VERSION 5.8 ;
BUSBITCHARS "[]" ;
DIVIDERCHAR "/" ;
UNITS
    DATABASE MICRONS 1000 ;
END UNITS

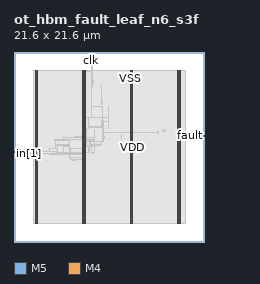
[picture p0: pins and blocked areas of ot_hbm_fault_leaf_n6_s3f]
MACRO ot_hbm_fault_leaf_n6_s3f
  FOREIGN ot_hbm_fault_leaf_n6_s3f 0 0 ;
  CLASS BLOCK ;
  SIZE 21.6 BY 21.6 ;
  PIN clk
    DIRECTION INPUT ;
    USE SIGNAL ;
    PORT
      LAYER M5 ;
        RECT  8.784 21.516 8.808 21.6 ;
    END
  END clk
  PIN fault
    DIRECTION OUTPUT ;
    USE SIGNAL ;
    PORT
      LAYER M4 ;
        RECT  21.516 12.048 21.6 12.072 ;
    END
    PORT
      LAYER M4 ;
        RECT  20.473 12.048 21.564 12.072 ;
    END
  END fault
  PIN in[0]
    DIRECTION INPUT ;
    USE SIGNAL ;
    PORT
      LAYER M4 ;
        RECT  0 9.936 0.084 9.96 ;
    END
  END in[0]
  PIN in[1]
    DIRECTION INPUT ;
    USE SIGNAL ;
    PORT
      LAYER M4 ;
        RECT  0 10.032 0.084 10.056 ;
    END
  END in[1]
  PIN in[2]
    DIRECTION INPUT ;
    USE SIGNAL ;
    PORT
      LAYER M4 ;
        RECT  0 10.128 0.084 10.152 ;
    END
  END in[2]
  PIN in[3]
    DIRECTION INPUT ;
    USE SIGNAL ;
    PORT
      LAYER M4 ;
        RECT  0 10.224 0.084 10.248 ;
    END
  END in[3]
  PIN in[4]
    DIRECTION INPUT ;
    USE SIGNAL ;
    PORT
      LAYER M4 ;
        RECT  0 10.32 0.084 10.344 ;
    END
  END in[4]
  PIN in[5]
    DIRECTION INPUT ;
    USE SIGNAL ;
    PORT
      LAYER M4 ;
        RECT  0 10.416 0.084 10.44 ;
    END
  END in[5]
  PIN rst_n
    DIRECTION INPUT ;
    USE SIGNAL ;
    PORT
      LAYER M5 ;
        RECT  8.88 21.516 8.904 21.6 ;
    END
  END rst_n
  PIN VDD
    DIRECTION INOUT ;
    USE POWER ;
    PORT
      LAYER M5 ;
        RECT  18.792 2.151 18.912 19.449 ;
        RECT  13.392 2.151 13.512 19.449 ;
        RECT  7.992 2.151 8.112 19.449 ;
        RECT  2.592 2.151 2.712 19.449 ;
    END
  END VDD
  PIN VSS
    DIRECTION INOUT ;
    USE GROUND ;
    PORT
      LAYER M5 ;
        RECT  18.6 2.137 18.72 19.463 ;
        RECT  13.2 2.137 13.32 19.463 ;
        RECT  7.8 2.137 7.92 19.463 ;
        RECT  2.4 2.137 2.52 19.463 ;
    END
  END VSS
  # OT_OBS_CLOSED layer=M5 d_um=1.536 added=2
  OBS
    LAYER RVTN ;
     RECT  2.16 2.16 19.44 2.295 ;
     RECT  2.16 2.565 19.44 2.835 ;
     RECT  2.16 3.105 19.44 3.375 ;
     RECT  2.16 3.645 19.44 3.915 ;
     RECT  2.16 4.185 19.44 4.455 ;
     RECT  2.16 4.725 19.44 4.995 ;
     RECT  2.16 5.265 19.44 5.535 ;
     RECT  2.16 5.805 19.44 6.075 ;
     RECT  2.16 6.345 19.44 6.615 ;
     RECT  2.16 6.885 19.44 7.155 ;
     RECT  2.16 7.425 19.44 7.695 ;
     RECT  2.16 7.965 19.44 8.235 ;
     RECT  2.16 8.505 19.44 8.775 ;
     RECT  2.16 9.045 19.44 9.315 ;
     RECT  2.16 9.585 19.44 9.855 ;
     RECT  2.16 10.125 19.44 10.395 ;
     RECT  2.16 10.665 19.44 10.935 ;
     RECT  2.16 11.205 19.44 11.475 ;
     RECT  2.16 11.745 19.44 12.015 ;
     RECT  2.16 12.285 19.44 12.555 ;
     RECT  2.16 12.825 19.44 13.095 ;
     RECT  2.16 13.365 19.44 13.635 ;
     RECT  2.16 13.905 19.44 14.175 ;
     RECT  2.16 14.445 19.44 14.715 ;
     RECT  2.16 14.985 19.44 15.255 ;
     RECT  2.16 15.525 19.44 15.795 ;
     RECT  2.16 16.065 19.44 16.335 ;
     RECT  2.16 16.605 19.44 16.875 ;
     RECT  2.16 17.145 19.44 17.415 ;
     RECT  2.16 17.685 19.44 17.955 ;
     RECT  2.16 18.225 19.44 18.495 ;
     RECT  2.16 18.765 19.44 19.035 ;
     RECT  2.16 19.305 19.44 19.44 ;
    LAYER RVTP ;
     RECT  2.16 2.295 19.44 2.565 ;
     RECT  2.16 2.835 19.44 3.105 ;
     RECT  2.16 3.375 19.44 3.645 ;
     RECT  2.16 3.915 19.44 4.185 ;
     RECT  2.16 4.455 19.44 4.725 ;
     RECT  2.16 4.995 19.44 5.265 ;
     RECT  2.16 5.535 19.44 5.805 ;
     RECT  2.16 6.075 19.44 6.345 ;
     RECT  2.16 6.615 19.44 6.885 ;
     RECT  2.16 7.155 19.44 7.425 ;
     RECT  2.16 7.695 19.44 7.965 ;
     RECT  2.16 8.235 19.44 8.505 ;
     RECT  2.16 8.775 19.44 9.045 ;
     RECT  2.16 9.315 19.44 9.585 ;
     RECT  2.16 9.855 19.44 10.125 ;
     RECT  2.16 10.395 19.44 10.665 ;
     RECT  2.16 10.935 19.44 11.205 ;
     RECT  2.16 11.475 19.44 11.745 ;
     RECT  2.16 12.015 19.44 12.285 ;
     RECT  2.16 12.555 19.44 12.825 ;
     RECT  2.16 13.095 19.44 13.365 ;
     RECT  2.16 13.635 19.44 13.905 ;
     RECT  2.16 14.175 19.44 14.445 ;
     RECT  2.16 14.715 19.44 14.985 ;
     RECT  2.16 15.255 19.44 15.525 ;
     RECT  2.16 15.795 19.44 16.065 ;
     RECT  2.16 16.335 19.44 16.605 ;
     RECT  2.16 16.875 19.44 17.145 ;
     RECT  2.16 17.415 19.44 17.685 ;
     RECT  2.16 17.955 19.44 18.225 ;
     RECT  2.16 18.495 19.44 18.765 ;
     RECT  2.16 19.035 19.44 19.305 ;
    LAYER M1 ;
     RECT  2.16 2.151 19.44 19.449 ;
    LAYER M2 ;
     RECT  2.16 2.151 19.44 19.449 ;
     RECT  19.44 12.186 20.507 12.204 ;
    LAYER M3 ;
     RECT  2.415 2.143 2.505 2.413 ;
     RECT  7.815 2.143 7.905 2.413 ;
     RECT  13.215 2.143 13.305 2.413 ;
     RECT  18.615 2.143 18.705 2.413 ;
     RECT  6.624 9.211 6.642 9.319 ;
     RECT  6.624 9.319 7.002 9.355 ;
     RECT  7.815 2.413 8.097 9.355 ;
     RECT  6.624 9.355 8.097 9.391 ;
     RECT  6.408 9.391 8.097 9.625 ;
     RECT  5.4 9.859 5.418 9.895 ;
     RECT  6.3 9.625 8.097 9.895 ;
     RECT  2.415 2.413 2.697 9.931 ;
     RECT  4.5 9.895 8.097 9.931 ;
     RECT  8.82 10.057 8.838 10.093 ;
     RECT  4.068 9.931 8.097 10.121 ;
     RECT  2.304 9.931 2.697 10.129 ;
     RECT  8.82 10.093 8.982 10.201 ;
     RECT  0.144 10.075 0.162 10.253 ;
     RECT  2.304 10.129 3.222 10.391 ;
     RECT  4.068 10.121 4.914 10.589 ;
     RECT  2.304 10.391 2.697 10.625 ;
     RECT  5.652 10.121 8.097 10.843 ;
     RECT  8.82 10.201 9.198 10.843 ;
     RECT  5.652 10.843 9.198 10.975 ;
     RECT  4.716 10.589 4.914 11.011 ;
     RECT  5.652 10.975 9.522 11.011 ;
     RECT  4.716 11.011 9.954 11.129 ;
     RECT  9.936 11.129 9.954 11.273 ;
     RECT  4.716 11.129 9.126 11.515 ;
     RECT  4.644 11.515 9.126 11.669 ;
     RECT  5.328 11.669 9.126 11.705 ;
     RECT  10.8 11.641 10.818 11.777 ;
     RECT  5.58 11.705 9.126 11.849 ;
     RECT  6.84 11.849 8.097 11.939 ;
     RECT  6.84 11.939 6.858 11.975 ;
     RECT  10.116 11.785 10.278 11.975 ;
     RECT  10.116 11.975 10.134 11.981 ;
     RECT  20.484 12.043 20.502 12.209 ;
     RECT  12.168 11.749 12.186 12.245 ;
     RECT  18.615 2.413 18.897 12.361 ;
     RECT  16.452 12.181 16.47 12.475 ;
     RECT  18.396 12.361 18.897 12.479 ;
     RECT  16.272 12.475 16.47 12.551 ;
     RECT  16.848 12.559 16.866 12.595 ;
     RECT  16.848 12.595 17.262 12.749 ;
     RECT  9.108 11.849 9.126 12.785 ;
     RECT  16.848 12.749 16.866 12.785 ;
     RECT  7.815 11.939 8.097 12.955 ;
     RECT  7.815 12.955 8.226 13.019 ;
     RECT  10.728 12.901 10.746 13.675 ;
     RECT  10.044 13.675 10.746 14.099 ;
     RECT  9.756 14.203 9.774 14.243 ;
     RECT  10.728 14.099 10.746 14.369 ;
     RECT  9.828 15.403 9.846 15.449 ;
     RECT  10.764 14.485 10.782 15.449 ;
     RECT  9.972 15.601 10.098 15.989 ;
     RECT  9.972 15.989 9.99 17.609 ;
     RECT  9.828 17.725 9.846 17.879 ;
     RECT  8.892 17.659 8.91 18.031 ;
     RECT  8.892 18.031 9.054 18.419 ;
     RECT  2.415 10.625 2.697 19.187 ;
     RECT  7.815 13.019 8.097 19.187 ;
     RECT  13.215 2.413 13.497 19.187 ;
     RECT  18.615 12.479 18.897 19.187 ;
     RECT  8.892 18.419 8.91 19.373 ;
     RECT  2.415 19.187 2.505 19.457 ;
     RECT  7.815 19.187 7.905 19.457 ;
     RECT  13.215 19.187 13.305 19.457 ;
     RECT  18.615 19.187 18.705 19.457 ;
    LAYER M4 ;
     RECT  0.084 9.936 2.408 9.96 ;
     RECT  0.06 9.96 2.408 10.032 ;
     RECT  0.084 10.032 2.408 10.056 ;
     RECT  0.06 10.056 2.408 10.128 ;
     RECT  0.084 10.128 2.408 10.152 ;
     RECT  0.06 10.152 2.408 10.224 ;
     RECT  0.084 10.224 2.408 10.248 ;
     RECT  0.06 10.248 2.408 10.32 ;
     RECT  0.084 10.32 2.408 10.344 ;
     RECT  0.06 10.344 2.408 10.416 ;
     RECT  0.084 10.416 2.408 10.44 ;
     RECT  2.408 2.148 2.512 19.452 ;
     RECT  2.512 2.418 2.704 19.182 ;
     RECT  2.704 10.032 4.529 10.296 ;
     RECT  4.529 10.08 4.853 10.296 ;
     RECT  4.853 10.08 4.925 10.152 ;
     RECT  4.925 10.08 6.289 10.104 ;
     RECT  6.289 10.08 6.373 10.632 ;
     RECT  5.353 11.664 7.369 11.688 ;
     RECT  6.373 10.08 7.808 10.104 ;
     RECT  7.369 11.424 7.808 11.688 ;
     RECT  7.808 2.148 7.912 19.452 ;
     RECT  7.912 2.418 8.104 19.368 ;
     RECT  8.104 10.224 8.243 11.688 ;
     RECT  8.104 12.96 8.435 13.08 ;
     RECT  8.243 10.224 8.531 11.448 ;
     RECT  8.531 10.848 8.705 11.448 ;
     RECT  8.104 17.664 8.921 17.688 ;
     RECT  8.104 19.344 8.921 19.368 ;
     RECT  8.104 14.208 9.785 14.232 ;
     RECT  8.435 13.056 9.989 13.08 ;
     RECT  8.705 11.424 10.021 11.448 ;
     RECT  9.989 13.056 10.067 13.8 ;
     RECT  9.817 15.408 10.067 15.432 ;
     RECT  10.067 13.68 10.073 13.8 ;
     RECT  10.021 11.424 10.076 11.832 ;
     RECT  10.076 11.424 10.117 11.976 ;
     RECT  10.117 11.424 10.163 12.504 ;
     RECT  10.073 13.776 10.163 13.8 ;
     RECT  10.163 12.48 13.208 12.504 ;
     RECT  13.208 2.148 13.312 19.452 ;
     RECT  13.312 2.418 13.504 19.182 ;
     RECT  13.504 12.48 16.301 12.504 ;
     RECT  18.608 2.148 18.712 19.452 ;
     RECT  18.712 2.418 18.904 19.182 ;
    LAYER M5 ;
     RECT  2.4 2.137 2.52 2.151 ;
     RECT  7.8 2.137 7.92 2.151 ;
     RECT  13.2 2.137 13.32 2.151 ;
     RECT  18.6 2.137 18.72 2.151 ;
     RECT  7.8 2.151 8.112 10.213 ;
     RECT  7.8 10.213 8.52 10.883 ;
     RECT  6.336 10.597 6.36 11.699 ;
     RECT  10.128 11.413 10.152 11.797 ;
     RECT  7.8 10.883 8.232 12.949 ;
     RECT  10.032 11.797 10.152 13.811 ;
     RECT  7.8 12.949 8.424 14.197 ;
     RECT  10.032 13.811 10.056 15.443 ;
     RECT  7.8 14.197 8.808 19.333 ;
     RECT  2.4 2.151 2.712 19.449 ;
     RECT  13.2 2.151 13.512 19.449 ;
     RECT  18.6 2.151 18.912 19.449 ;
     RECT  2.4 19.449 2.52 19.463 ;
     RECT  7.8 19.333 8.904 19.463 ;
     RECT  13.2 19.449 13.32 19.463 ;
     RECT  18.6 19.449 18.72 19.463 ;
     RECT  8.784 19.463 8.904 21.516 ;
     RECT  8.808 21.516 8.88 21.584 ;
     RECT  6.36 10.597 7.8 11.699 ;
     RECT  8.808 14.197 10.032 15.443 ;
  END
END ot_hbm_fault_leaf_n6_s3f
END LIBRARY
